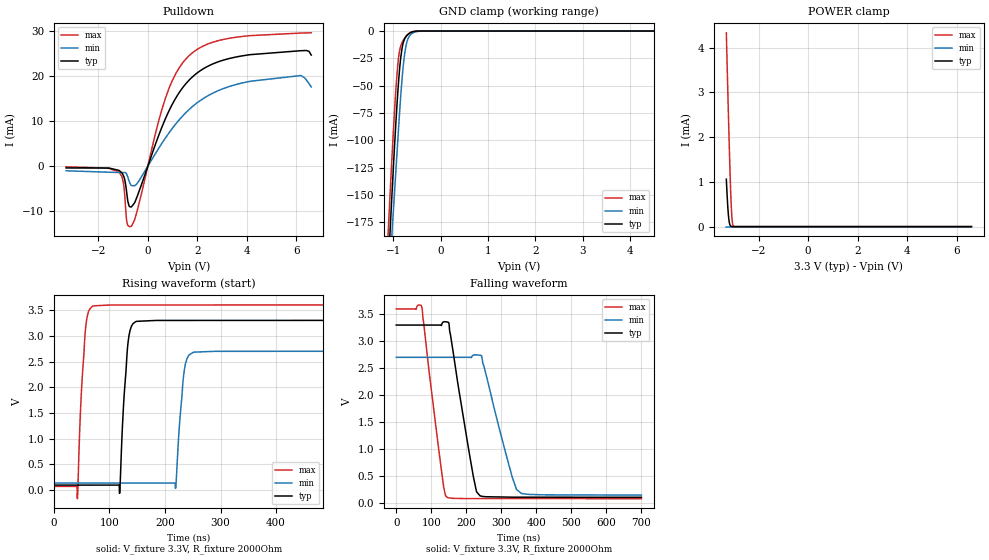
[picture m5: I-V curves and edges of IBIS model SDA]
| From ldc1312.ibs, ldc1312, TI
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|   Model
[Model]   SDA
Model_type   I/O_open_drain
Polarity   Non-Inverting
Enable   Active-Low
Vinl = 0.99
Vinh = 2.51
Vmeas = 1.65
Vref = 3.3
Cref = 1pF
Rref = 2000
|   typ   min   max
C_comp   0.789pF   0.765pF   0.820pF
[Voltage Range]   3.3   2.7   3.6
[Temperature Range]   27   125   -40
[Pullup Reference]   3.3   2.7   3.6
[Pulldown Reference]   0   -0   0
[Power Clamp Reference]   3.3   2.7   3.6
[GND Clamp Reference]   0   0   0
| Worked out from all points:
|   slope of the pulldown table from 0 to 0.495 V, typ, clamps not added: 64.8 ohm
|   GND clamp passes 1 mA (typ) near -0.61 V on its own axis
|   POWER clamp passes 1 mA (typ) near -3.29 V on its own axis
|   falling waveform, V_fixture 3.3V, R_fixture 2000Ohm: 20-80 % time 47.7ns typ, 60ns min, 39.6ns max; typ from 3.3 V to 0.099 V
|   rising waveform, V_fixture 3.3V, R_fixture 2000Ohm: 20-80 % time 10.3ns typ, 10.6ns min, 10ns max; typ from 0.1 V to 3.3 V
[Pulldown]
|   Voltage   I(typ)   I(min)   I(max)
-3.3V     -373.1uA   -999.7uA   -123uA
-1.162V   -927.1uA   -1.382mA   -1.288mA
-983.4mV  -2.074mA   -1.403mA   -3.764mA
-844.8mV  -6.166mA   -1.873mA   -12.4mA
-676.5mV  -9.031mA   -4.199mA   -13.34mA
-448.8mV  -6.98mA    -3.935mA   -10.26mA
709.5mV   10.54mA    6.261mA    15.06mA
1.541V    18.35mA    11.93mA    23.84mA
2.511V    22.44mA    15.91mA    27.32mA
4.036V    24.7mA     18.76mA    28.94mA
6.174V    25.65mA    20.14mA    29.57mA
6.6V      24.68mA    17.62mA    29.62mA
[GND Clamp]
|   Voltage   I(typ)   I(min)   I(max)
-3.3V     -2.304A    -1.759A    -2.318A
-1.132V   -237mA     -254.8mA   -203.2mA
-1.073V   -184.8mA   -213.9mA   -150.8mA
-1.053V   -167.9mA   -200.3mA   -133.9mA
-1.013V   -134.8mA   -173mA     -101.3mA
-924mV    -67.13mA   -111.6mA   -39.22mA
-884.4mV  -42.63mA   -84.4mA    -22.17mA
-844.8mV  -24.16mA   -59.05mA   -13.55mA
-795.3mV  -11.2mA    -33.34mA   -8.665mA
-745.8mV  -5.857mA   -16.32mA   -5.545mA
-617.1mV  -1.059mA   -2.492mA   -837.3uA
6.6V      0A         0A         0A
[POWER Clamp]
|   Voltage   I(typ)   I(min)   I(max)
-3.3V     1.06mA     3.238nA    4.332mA
-3.251V   527.1uA    0A         3.247mA
-3.211V   226.3uA    0A         2.404mA
-3.191V   130.8uA    0A         1.998mA
-3.161V   49.89uA    0A         1.42mA
-3.142V   24.57uA    0A         1.064mA
-3.122V   11.76uA    0A         743.9uA
-3.092V   3.787uA    0A         359.6uA
-3.072V   1.761uA    0A         187.8uA
-3.043V   549nA      0A         55.46uA
-3.003V   106.1nA    0A         8.459uA
6.6V      0A         0A         0A
[Ramp]
R_load = 2000
|   typ   min   max
dV/dt_r   1.92021/1.02903e-08   1.53665/1.06045e-08   2.11612/9.99613e-09
dV/dt_f   1.92038/4.76788e-08   1.53634/5.99255e-08   2.11617/3.95888e-08
[Falling Waveform]
V_fixture = 3.3V
V_fixture_min = 2.7V
V_fixture_max = 3.6V
R_fixture = 2000Ohm
C_fixture = 0F
|   Time   V(typ)   V(min)   V(max)
0s        3.3V       2.7V       3.6V
72.01ns   3.3V       2.7V       3.664V
133.7ns   3.354V     2.7V       377.5mV
145.1ns   3.357V     2.7V       98.81mV
150.9ns   3.319V     2.7V       86.92mV
220.5ns   477.3mV    2.741V     75.44mV
229.4ns   201.4mV    2.746V     75.4mV
239.7ns   124.6mV    2.738V     75.35mV
343.6ns   101.1mV    243.6mV    74.82mV
700ns     99.3mV     139.8mV    73.01mV
[Rising Waveform]
V_fixture = 3.3V
V_fixture_min = 2.7V
V_fixture_max = 3.6V
R_fixture = 2000Ohm
C_fixture = 0F
|   Time   V(typ)   V(min)   V(max)
0s        99.54mV    139.2mV    73.07mV
42.43ns   99.59mV    139.2mV    -164.7mV
56.1ns    99.6mV     139.2mV    3.019V
68.56ns   99.61mV    139.2mV    3.566V
118.4ns   -60.15mV   139.2mV    3.599V
132.7ns   2.777V     139.2mV    3.599V
147.1ns   3.273V     139.2mV    3.599V
219ns     3.299V     34.41mV    3.599V
250.5ns   3.299V     2.677V     3.599V
700ns     3.3V       2.7V       3.6V
